VERSION 5.7 ;
  NOWIREEXTENSIONATPIN ON ;
  DIVIDERCHAR "/" ;
  BUSBITCHARS "[]" ;
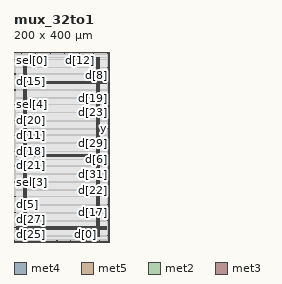
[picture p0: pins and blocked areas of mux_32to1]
MACRO mux_32to1
  CLASS BLOCK ;
  FOREIGN mux_32to1 ;
  ORIGIN 0.000 0.000 ;
  SIZE 200.000 BY 400.000 ;
  PIN VGND
    DIRECTION INOUT ;
    USE GROUND ;
    PORT
      LAYER met4 ;
        RECT 24.340 10.640 25.940 389.200 ;
    END
    PORT
      LAYER met4 ;
        RECT 177.940 10.640 179.540 389.200 ;
    END
    PORT
      LAYER met5 ;
        RECT 5.280 30.030 194.360 31.630 ;
    END
    PORT
      LAYER met5 ;
        RECT 5.280 183.210 194.360 184.810 ;
    END
    PORT
      LAYER met5 ;
        RECT 5.280 336.390 194.360 337.990 ;
    END
  END VGND
  PIN VPWR
    DIRECTION INOUT ;
    USE POWER ;
    PORT
      LAYER met4 ;
        RECT 21.040 10.640 22.640 389.200 ;
    END
    PORT
      LAYER met4 ;
        RECT 174.640 10.640 176.240 389.200 ;
    END
    PORT
      LAYER met5 ;
        RECT 5.280 26.730 194.360 28.330 ;
    END
    PORT
      LAYER met5 ;
        RECT 5.280 179.910 194.360 181.510 ;
    END
    PORT
      LAYER met5 ;
        RECT 5.280 333.090 194.360 334.690 ;
    END
  END VPWR
  PIN d[0]
    DIRECTION INPUT ;
    USE SIGNAL ;
    ANTENNAGATEAREA 0.213000 ;
    PORT
      LAYER met2 ;
        RECT 151.430 0.000 151.710 4.000 ;
    END
  END d[0]
  PIN d[10]
    DIRECTION INPUT ;
    USE SIGNAL ;
    ANTENNAGATEAREA 0.196500 ;
    PORT
      LAYER met3 ;
        RECT 0.000 95.240 4.000 95.840 ;
    END
  END d[10]
  PIN d[11]
    DIRECTION INPUT ;
    USE SIGNAL ;
    ANTENNAGATEAREA 0.196500 ;
    PORT
      LAYER met3 ;
        RECT 0.000 224.440 4.000 225.040 ;
    END
  END d[11]
  PIN d[12]
    DIRECTION INPUT ;
    USE SIGNAL ;
    ANTENNAGATEAREA 0.196500 ;
    PORT
      LAYER met2 ;
        RECT 138.550 396.000 138.830 400.000 ;
    END
  END d[12]
  PIN d[13]
    DIRECTION INPUT ;
    USE SIGNAL ;
    ANTENNAGATEAREA 0.196500 ;
    PORT
      LAYER met2 ;
        RECT 77.370 396.000 77.650 400.000 ;
    END
  END d[13]
  PIN d[14]
    DIRECTION INPUT ;
    USE SIGNAL ;
    ANTENNAGATEAREA 0.196500 ;
    PORT
      LAYER met2 ;
        RECT 106.350 396.000 106.630 400.000 ;
    END
  END d[14]
  PIN d[15]
    DIRECTION INPUT ;
    USE SIGNAL ;
    ANTENNAGATEAREA 0.196500 ;
    PORT
      LAYER met3 ;
        RECT 0.000 353.640 4.000 354.240 ;
    END
  END d[15]
  PIN d[16]
    DIRECTION INPUT ;
    USE SIGNAL ;
    ANTENNAGATEAREA 0.126000 ;
    PORT
      LAYER met3 ;
        RECT 196.000 78.240 200.000 78.840 ;
    END
  END d[16]
  PIN d[17]
    DIRECTION INPUT ;
    USE SIGNAL ;
    ANTENNAGATEAREA 0.213000 ;
    PORT
      LAYER met3 ;
        RECT 196.000 44.240 200.000 44.840 ;
    END
  END d[17]
  PIN d[18]
    DIRECTION INPUT ;
    USE SIGNAL ;
    ANTENNAGATEAREA 0.196500 ;
    PORT
      LAYER met3 ;
        RECT 0.000 190.440 4.000 191.040 ;
    END
  END d[18]
  PIN d[19]
    DIRECTION INPUT ;
    USE SIGNAL ;
    ANTENNAGATEAREA 0.126000 ;
    PORT
      LAYER met3 ;
        RECT 196.000 302.640 200.000 303.240 ;
    END
  END d[19]
  PIN d[1]
    DIRECTION INPUT ;
    USE SIGNAL ;
    ANTENNAGATEAREA 0.159000 ;
    PORT
      LAYER met3 ;
        RECT 0.000 384.240 4.000 384.840 ;
    END
  END d[1]
  PIN d[20]
    DIRECTION INPUT ;
    USE SIGNAL ;
    ANTENNAGATEAREA 0.196500 ;
    PORT
      LAYER met3 ;
        RECT 0.000 255.040 4.000 255.640 ;
    END
  END d[20]
  PIN d[21]
    DIRECTION INPUT ;
    USE SIGNAL ;
    ANTENNAGATEAREA 0.196500 ;
    PORT
      LAYER met3 ;
        RECT 0.000 159.840 4.000 160.440 ;
    END
  END d[21]
  PIN d[22]
    DIRECTION INPUT ;
    USE SIGNAL ;
    ANTENNAGATEAREA 0.126000 ;
    PORT
      LAYER met3 ;
        RECT 196.000 108.840 200.000 109.440 ;
    END
  END d[22]
  PIN d[23]
    DIRECTION INPUT ;
    USE SIGNAL ;
    ANTENNAGATEAREA 0.196500 ;
    PORT
      LAYER met3 ;
        RECT 196.000 272.040 200.000 272.640 ;
    END
  END d[23]
  PIN d[24]
    DIRECTION INPUT ;
    USE SIGNAL ;
    ANTENNAGATEAREA 0.213000 ;
    PORT
      LAYER met3 ;
        RECT 196.000 336.640 200.000 337.240 ;
    END
  END d[24]
  PIN d[25]
    DIRECTION INPUT ;
    USE SIGNAL ;
    ANTENNAGATEAREA 0.159000 ;
    PORT
      LAYER met2 ;
        RECT 0.090 0.000 0.370 4.000 ;
    END
  END d[25]
  PIN d[26]
    DIRECTION INPUT ;
    USE SIGNAL ;
    ANTENNAGATEAREA 0.213000 ;
    PORT
      LAYER met3 ;
        RECT 0.000 319.640 4.000 320.240 ;
    END
  END d[26]
  PIN d[27]
    DIRECTION INPUT ;
    USE SIGNAL ;
    ANTENNAGATEAREA 0.213000 ;
    PORT
      LAYER met3 ;
        RECT 0.000 30.640 4.000 31.240 ;
    END
  END d[27]
  PIN d[28]
    DIRECTION INPUT ;
    USE SIGNAL ;
    ANTENNAGATEAREA 0.213000 ;
    PORT
      LAYER met2 ;
        RECT 90.250 0.000 90.530 4.000 ;
    END
  END d[28]
  PIN d[29]
    DIRECTION INPUT ;
    USE SIGNAL ;
    ANTENNAGATEAREA 0.196500 ;
    PORT
      LAYER met3 ;
        RECT 196.000 207.440 200.000 208.040 ;
    END
  END d[29]
  PIN d[2]
    DIRECTION INPUT ;
    USE SIGNAL ;
    ANTENNAGATEAREA 0.213000 ;
    PORT
      LAYER met3 ;
        RECT 196.000 13.640 200.000 14.240 ;
    END
  END d[2]
  PIN d[30]
    DIRECTION INPUT ;
    USE SIGNAL ;
    ANTENNAGATEAREA 0.213000 ;
    PORT
      LAYER met2 ;
        RECT 167.530 396.000 167.810 400.000 ;
    END
  END d[30]
  PIN d[31]
    DIRECTION INPUT ;
    USE SIGNAL ;
    ANTENNAGATEAREA 0.196500 ;
    PORT
      LAYER met3 ;
        RECT 196.000 142.840 200.000 143.440 ;
    END
  END d[31]
  PIN d[3]
    DIRECTION INPUT ;
    USE SIGNAL ;
    ANTENNAGATEAREA 0.213000 ;
    PORT
      LAYER met2 ;
        RECT 29.070 0.000 29.350 4.000 ;
    END
  END d[3]
  PIN d[4]
    DIRECTION INPUT ;
    USE SIGNAL ;
    ANTENNAGATEAREA 0.126000 ;
    PORT
      LAYER met2 ;
        RECT 58.050 0.000 58.330 4.000 ;
    END
  END d[4]
  PIN d[5]
    DIRECTION INPUT ;
    USE SIGNAL ;
    ANTENNAGATEAREA 0.126000 ;
    PORT
      LAYER met3 ;
        RECT 0.000 61.240 4.000 61.840 ;
    END
  END d[5]
  PIN d[6]
    DIRECTION INPUT ;
    USE SIGNAL ;
    ANTENNAGATEAREA 0.196500 ;
    PORT
      LAYER met3 ;
        RECT 196.000 173.440 200.000 174.040 ;
    END
  END d[6]
  PIN d[7]
    DIRECTION INPUT ;
    USE SIGNAL ;
    ANTENNAGATEAREA 0.126000 ;
    PORT
      LAYER met2 ;
        RECT 119.230 0.000 119.510 4.000 ;
    END
  END d[7]
  PIN d[8]
    DIRECTION INPUT ;
    USE SIGNAL ;
    ANTENNAGATEAREA 0.196500 ;
    PORT
      LAYER met3 ;
        RECT 196.000 367.240 200.000 367.840 ;
    END
  END d[8]
  PIN d[9]
    DIRECTION INPUT ;
    USE SIGNAL ;
    ANTENNAGATEAREA 0.196500 ;
    PORT
      LAYER met2 ;
        RECT 196.510 396.000 196.790 400.000 ;
    END
  END d[9]
  PIN sel[0]
    DIRECTION INPUT ;
    USE SIGNAL ;
    ANTENNAGATEAREA 0.213000 ;
    PORT
      LAYER met2 ;
        RECT 16.190 396.000 16.470 400.000 ;
    END
  END sel[0]
  PIN sel[1]
    DIRECTION INPUT ;
    USE SIGNAL ;
    ANTENNAGATEAREA 0.247500 ;
    PORT
      LAYER met2 ;
        RECT 45.170 396.000 45.450 400.000 ;
    END
  END sel[1]
  PIN sel[2]
    DIRECTION INPUT ;
    USE SIGNAL ;
    ANTENNAGATEAREA 0.213000 ;
    PORT
      LAYER met2 ;
        RECT 180.410 0.000 180.690 4.000 ;
    END
  END sel[2]
  PIN sel[3]
    DIRECTION INPUT ;
    USE SIGNAL ;
    ANTENNAGATEAREA 0.159000 ;
    PORT
      LAYER met3 ;
        RECT 0.000 125.840 4.000 126.440 ;
    END
  END sel[3]
  PIN sel[4]
    DIRECTION INPUT ;
    USE SIGNAL ;
    ANTENNAGATEAREA 0.126000 ;
    PORT
      LAYER met3 ;
        RECT 0.000 289.040 4.000 289.640 ;
    END
  END sel[4]
  PIN y
    DIRECTION OUTPUT TRISTATE ;
    USE SIGNAL ;
    ANTENNADIFFAREA 0.445500 ;
    PORT
      LAYER met3 ;
        RECT 196.000 238.040 200.000 238.640 ;
    END
  END y
  OBS
      LAYER li1 ;
        RECT 5.520 10.795 194.120 389.045 ;
      LAYER met1 ;
        RECT 0.070 10.640 196.810 389.200 ;
      LAYER met2 ;
        RECT 0.100 395.720 15.910 396.000 ;
        RECT 16.750 395.720 44.890 396.000 ;
        RECT 45.730 395.720 77.090 396.000 ;
        RECT 77.930 395.720 106.070 396.000 ;
        RECT 106.910 395.720 138.270 396.000 ;
        RECT 139.110 395.720 167.250 396.000 ;
        RECT 168.090 395.720 196.230 396.000 ;
        RECT 0.100 4.280 196.780 395.720 ;
        RECT 0.650 4.000 28.790 4.280 ;
        RECT 29.630 4.000 57.770 4.280 ;
        RECT 58.610 4.000 89.970 4.280 ;
        RECT 90.810 4.000 118.950 4.280 ;
        RECT 119.790 4.000 151.150 4.280 ;
        RECT 151.990 4.000 180.130 4.280 ;
        RECT 180.970 4.000 196.780 4.280 ;
      LAYER met3 ;
        RECT 3.990 385.240 196.000 389.125 ;
        RECT 4.400 383.840 196.000 385.240 ;
        RECT 3.990 368.240 196.000 383.840 ;
        RECT 3.990 366.840 195.600 368.240 ;
        RECT 3.990 354.640 196.000 366.840 ;
        RECT 4.400 353.240 196.000 354.640 ;
        RECT 3.990 337.640 196.000 353.240 ;
        RECT 3.990 336.240 195.600 337.640 ;
        RECT 3.990 320.640 196.000 336.240 ;
        RECT 4.400 319.240 196.000 320.640 ;
        RECT 3.990 303.640 196.000 319.240 ;
        RECT 3.990 302.240 195.600 303.640 ;
        RECT 3.990 290.040 196.000 302.240 ;
        RECT 4.400 288.640 196.000 290.040 ;
        RECT 3.990 273.040 196.000 288.640 ;
        RECT 3.990 271.640 195.600 273.040 ;
        RECT 3.990 256.040 196.000 271.640 ;
        RECT 4.400 254.640 196.000 256.040 ;
        RECT 3.990 239.040 196.000 254.640 ;
        RECT 3.990 237.640 195.600 239.040 ;
        RECT 3.990 225.440 196.000 237.640 ;
        RECT 4.400 224.040 196.000 225.440 ;
        RECT 3.990 208.440 196.000 224.040 ;
        RECT 3.990 207.040 195.600 208.440 ;
        RECT 3.990 191.440 196.000 207.040 ;
        RECT 4.400 190.040 196.000 191.440 ;
        RECT 3.990 174.440 196.000 190.040 ;
        RECT 3.990 173.040 195.600 174.440 ;
        RECT 3.990 160.840 196.000 173.040 ;
        RECT 4.400 159.440 196.000 160.840 ;
        RECT 3.990 143.840 196.000 159.440 ;
        RECT 3.990 142.440 195.600 143.840 ;
        RECT 3.990 126.840 196.000 142.440 ;
        RECT 4.400 125.440 196.000 126.840 ;
        RECT 3.990 109.840 196.000 125.440 ;
        RECT 3.990 108.440 195.600 109.840 ;
        RECT 3.990 96.240 196.000 108.440 ;
        RECT 4.400 94.840 196.000 96.240 ;
        RECT 3.990 79.240 196.000 94.840 ;
        RECT 3.990 77.840 195.600 79.240 ;
        RECT 3.990 62.240 196.000 77.840 ;
        RECT 4.400 60.840 196.000 62.240 ;
        RECT 3.990 45.240 196.000 60.840 ;
        RECT 3.990 43.840 195.600 45.240 ;
        RECT 3.990 31.640 196.000 43.840 ;
        RECT 4.400 30.240 196.000 31.640 ;
        RECT 3.990 14.640 196.000 30.240 ;
        RECT 3.990 13.240 195.600 14.640 ;
        RECT 3.990 10.715 196.000 13.240 ;
  END
END mux_32to1
END LIBRARY

